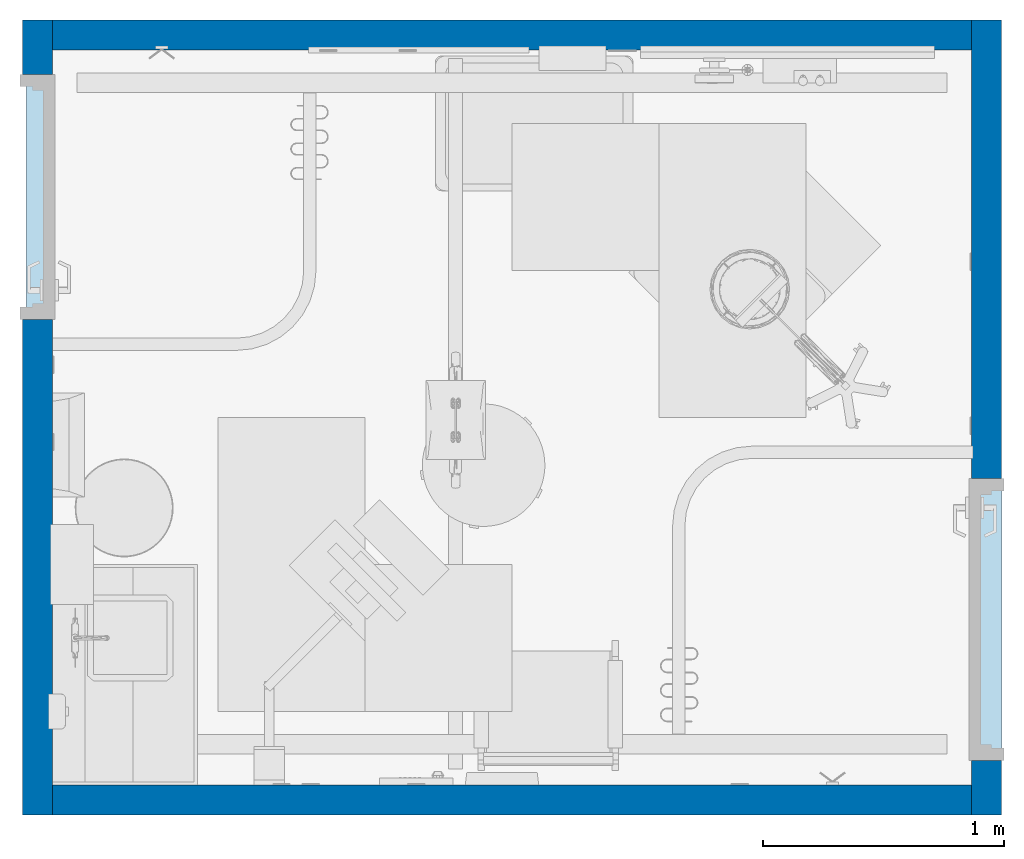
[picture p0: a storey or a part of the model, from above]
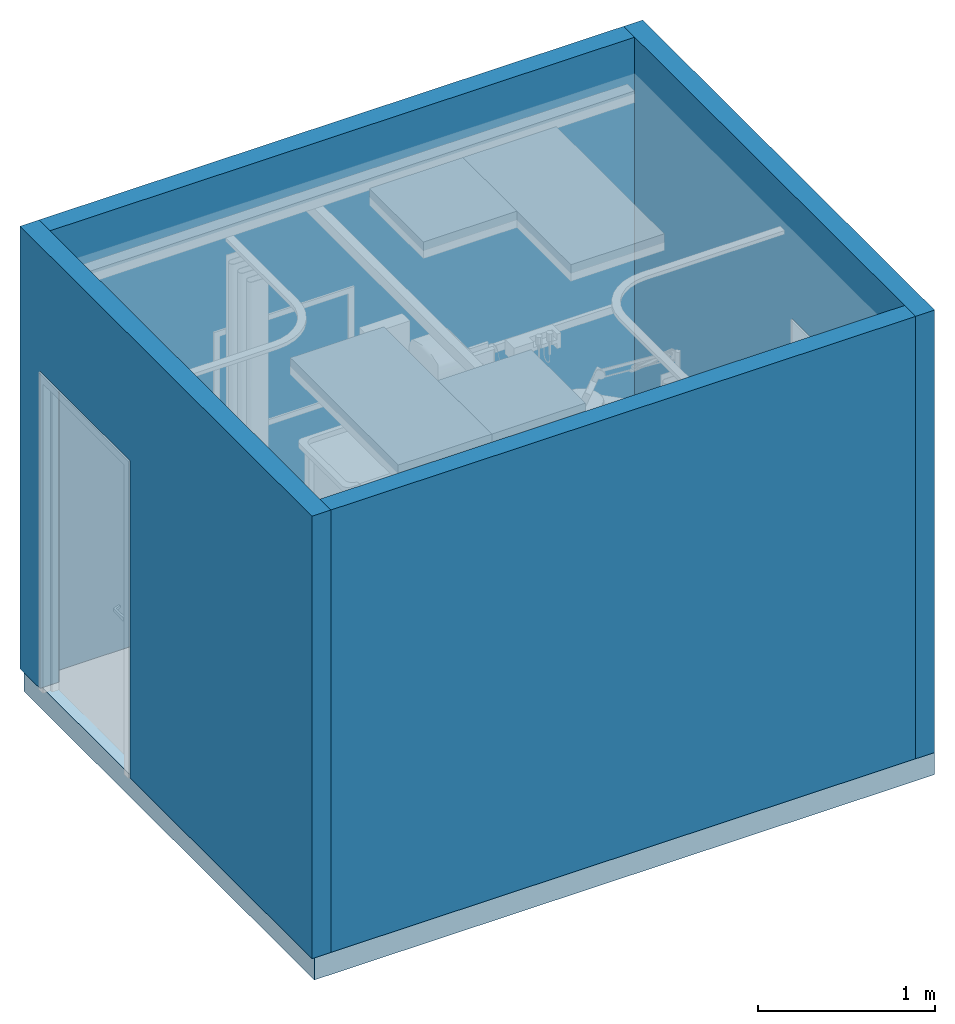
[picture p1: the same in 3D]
Properties of the parts of a building model (IFC2X3)

# File
Description: ViewDefinition [CoordinationView_V2.0]
File name: (ROOM CODE)
Time: 2018-06-27T14:00:12
Written by: The EXPRESS Data Manager Version 5.02.0100.07 : 28 Aug 2013
Made in: 20170223_1515(x64) - Exporter 18.0.0.420 - Alternate UI 18.0.0.420
Comment: STEP Physical File produced by: The EXPRESS Data Manager Version 5.02.0100.07 : 28 Aug 2013 * Module: EDMstepFileFactory/EDMstandAlone * Creation date: Wed Jun 27 14:00:12 2018 * Host: L106-OKC * Database: C:\Users\BHR~1.SPU\AppData\Local\Temp\{045EDBB5-DE35-4E17-B63D-0D913D50125E}\ifc * Database version: 5507 * Database creation date: Wed Jun 27 14:00:10 2018 * Schema: IFC2X3 * Model: DataRepository.ifc * Model creation date: Wed Jun 27 14:00:10 2018 * Header model: DataRepository.ifc_HeaderModel * Header model creation date: Wed Jun 27 14:00:10 2018 * EDMuser: sdai-user * EDMgroup: sdai-group * License ID and type: 5605 : Permanent license. Expiry date: * EDMstepFileFactory options: 020000

# IfcProject, (ROOM CODE)
LongName: ROOM NAME (ROOM CODE); Phase: DRAFT

# IfcSite, Default
RefLatitude: 42, 21, 31, 181945; RefLongitude: -71, -3, -24, -263305; RefElevation: 0 ft

# IfcBuilding, OUTPATIENT / PACT CLINIC (Ch. 265)
LongName: OUTPATIENT / PACT CLINIC (Ch. 265)
Pset_BuildingCommon - NumberOfStoreys: 1

# IfcBuildingStorey, DATUM
In: OUTPATIENT / PACT CLINIC (Ch. 265)
LongName: DATUM; Elevation: 0 ft

# IfcSpace, EXPA1
In: DATUM
LongName: EXAM ROOM-PATIENT ALIGNED CARE TEAM; InteriorOrExteriorSpace: INTERNAL
Pset_SpaceCommon - Reference: EXAM ROOM-PATIENT ALIGNED CARE TEAM EXPA1; Category: Rooms

# IfcBuildingElementProxy: 24" x 24", Supply Diffuser:24" x 24":721201
In: EXPA1
Type - Classification: D3040100 Air Distribution Systems (Uniformat)
Pset_BuildingElementProxyCommon - Reference: 24" x 24"

# IfcBuildingElementProxy: 24" x 24", Return Register:24" x 24":721202
In: EXPA1
Type - Classification: D3040200 Exhaust Ventilation Systems (Uniformat)
Pset_BuildingElementProxyCommon - Reference: 24" x 24"

# IfcBuildingElementProxy: 24"H x 24"D x 36"W, Z1018 - Cabinet, ADA Sink Support:24"H x 24"D x 36"W:1427568
In: EXPA1
Type - Classification: CC (Uniformat)
Pset_BuildingElementProxyCommon - Reference: 24"H x 24"D x 36"W
Pset_ManufacturerTypeInformation - Manufacturer: Herman Miller, Inc.

# IfcBuildingElementProxy: A1012 - Telephone, Wall Mounted, 1 Line 12'' x 12'', A1012 - Telephone, Wall Mounted, 1 Line:A1012 - Telephone, Wall Mounted, 1 Line 12'' x 12'':721190
In: EXPA1
Type - Classification: VV (Uniformat)
Pset_BuildingElementProxyCommon - Reference: A1012 - Telephone, Wall Mounted, 1 Line 12'' x 12''

# IfcBuildingElementProxy: A1132 - Rail, Accessory Mounting, A1132 - Rail, Accessory Mounting:A1132 - Rail, Accessory Mounting:721204
In: EXPA1
Type - Classification: VC (Uniformat)
Pset_BuildingElementProxyCommon - Reference: A1132 - Rail, Accessory Mounting

# IfcBuildingElementProxy: A1203 Lift System, Overhead, Bariatric, A1203 Lift System, Overhead, Bariatric (Traverse):A1203 Lift System, Overhead, Bariatric:1360987
In: EXPA1
Type - Classification: CC (Uniformat)
Pset_BuildingElementProxyCommon - Reference: A1203 Lift System, Overhead, Bariatric

# IfcBuildingElementProxy: A5075 - Dispenser, Soap, A5075 - Dispenser, Soap:A5075 - Dispenser, Soap:721176
In: EXPA1
Type - Classification: VV (Uniformat)
Pset_BuildingElementProxyCommon - Reference: A5075 - Dispenser, Soap

# IfcBuildingElementProxy: A5080 - Dispenser, Paper Towel, A5080 - Dispenser, Paper Towel:A5080 - Dispenser, Paper Towel:721177
In: EXPA1
Type - Classification: CC (Uniformat)
Pset_BuildingElementProxyCommon - Reference: A5080 - Dispenser, Paper Towel

# IfcBuildingElementProxy: A5107 - Dispenser, Glove, Surgical-Examination, Wall Mntd 10"x 4", A5107 - Dispenser, Glove, Surgical-Examination, Wall Mntd:A5107 - Dispenser, Glove, Surgical-Examination, Wall Mntd 10"x 4":721206
In: EXPA1
Classification: VV (Uniformat)
Pset_BuildingElementProxyCommon - Reference: A5107 - Dispenser, Glove, Surgical-Examination, Wall Mntd 10"x 4"

# IfcBuildingElementProxy: A5108 - Waste Disposal Unit, Sharps 17"x 13", A5108 - Waste Disposal Unit, Sharps:A5108 - Waste Disposal Unit, Sharps 17"x 13":1367652
In: DATUM
Type - Classification: VV (Uniformat)
Pset_BuildingElementProxyCommon - Reference: A5108 - Waste Disposal Unit, Sharps 17"x 13"

# IfcBuildingElementProxy: A5145 - Hook, Garment, Double (2)
In: EXPA1
Type - Classification: CC (Uniformat)
Pset_BuildingElementProxyCommon - Reference: A5145 - Hook, Garment, Double
Name (A5145 - Hook, Garment, Double:A5145 - Hook, Garment, Double:...)
721192
721203

# IfcBuildingElementProxy: A5180 - Track, Cubicle, Surface Mounted, With Curtain, Curved (2)
In: EXPA1
Type - Classification: CC (Uniformat)
Pset_BuildingElementProxyCommon - Reference: A5180 - Track, Cubicle, Surface Mounted, With Curtain, Curved
Name (A5180 - Track, Cubicle, Surface Mounted, With Curtain, Corner:A5180 - Track, Cubicle, Surface Mounted, With Curtain, Curved:...)
721171
721197

# IfcBuildingElementProxy: CD040 - Cabinet, W-H, 2 Shelf, 2 DO, Sloping Top, 38x36x13, CD040 - Cabinet, W-H, 2 Shelf, 2 DO, Sloping Top, 38x36x13:CD040 - Cabinet, W-H, 2 Shelf, 2 DO, Sloping Top, 38x36x13:721159
In: EXPA1
Type - Classification: CC (Uniformat)
Pset_BuildingElementProxyCommon - Reference: CD040 - Cabinet, W-H, 2 Shelf, 2 DO, Sloping Top, 38x36x13

# IfcBuildingElementProxy: CS010 - Sink, SS, Single Compartment, 7.5x12x12 ID, CS010 - Sink, SS, Single Compartment, 7.5x12x12 ID:CS010 - Sink, SS, Single Compartment, 7.5x12x12 ID:721198
In: EXPA1
Type - Classification: CC (Uniformat)
Pset_BuildingElementProxyCommon - Reference: CS010 - Sink, SS, Single Compartment, 7.5x12x12 ID

# IfcBuildingElementProxy: CT020 - Countertop, Solid Surface - No Opening (1), CT020 - Countertop, Solid Surface - No Opening (1):CT020 - Countertop, Solid Surface - No Opening (1):721196
In: EXPA1
Type - Classification: CC (Uniformat)
Pset_BuildingElementProxyCommon - Reference: CT020 - Countertop, Solid Surface - No Opening (1)

# IfcBuildingElementProxy: Dimmer (2)
In: EXPA1
Pset_BuildingElementProxyCommon - Reference: Dimmer
Name (Switch, Dimmer:Dimmer:...)
1554813
1554932

# IfcBuildingElementProxy: Duplex (5)
In: EXPA1
Pset_BuildingElementProxyCommon - Reference: Duplex
Name (Outlet, Duplex, Wall:Duplex:...)
1554962
1554978
1554994
1555037
1682465

# IfcBuildingElementProxy: E0948 - Cart, General Storage, Mobile 42x32x22, E0948 - Cart, General Storage, Mobile 42x32x22:E0948 - Cart, General Storage, Mobile 42x32x22:721178
In: EXPA1
Type - Classification: VV (Uniformat)
Pset_BuildingElementProxyCommon - Reference: E0948 - Cart, General Storage, Mobile 42x32x22

# IfcBuildingElementProxy: Exam/Treatment Table with Cabinet, M9025 - Exam Table:Exam/Treatment Table with Cabinet:721184
In: EXPA1
Type - Classification: VV (Uniformat)
Pset_BuildingElementProxyCommon - Reference: Exam/Treatment Table with Cabinet

# IfcBuildingElementProxy: F0205 - Chair, Side With Arms, F0205 - Chair, Side With Arms:F0205 - Chair, Side With Arms:721193
In: EXPA1
Type - Classification: VV (Uniformat)
Pset_BuildingElementProxyCommon - Reference: F0205 - Chair, Side With Arms

# IfcBuildingElementProxy: F0340 - Stool, Self Adjusting, F0340 - Stool, Self Adjusting:F0340 - Stool, Self Adjusting:721179
In: EXPA1
Type - Classification: VV (Uniformat)
Pset_BuildingElementProxyCommon - Reference: F0340 - Stool, Self Adjusting

# IfcBuildingElementProxy: F2000 - Basket, Wastepaper, F2000 - Basket, Wastepaper:F2000 - Basket, Wastepaper:721180
In: EXPA1
Type - Classification: VV (Uniformat)
Pset_BuildingElementProxyCommon - Reference: F2000 - Basket, Wastepaper

# IfcBuildingElementProxy: F3025 - Board, Bulletin, Wood Framed, F3025 - Board, Bulletin, Wood Framed:F3025 - Board, Bulletin, Wood Framed:721172
In: DATUM
Type - Classification: VV (Uniformat)
Pset_BuildingElementProxyCommon - Reference: F3025 - Board, Bulletin, Wood Framed

# IfcBuildingElementProxy: F3200 - Clock, Battery, 12in Dia, F3200 - Clock, Battery, 12in Dia:F3200 - Clock, Battery, 12in Dia:721181
In: EXPA1
Type - Classification: VV (Uniformat)
Pset_BuildingElementProxyCommon - Reference: F3200 - Clock, Battery, 12in Dia

# IfcBuildingElementProxy: Hoist, Hoist:Hoist:1360988
In: EXPA1
Pset_BuildingElementProxyCommon - Reference: Hoist

# IfcBuildingElementProxy: M1801 - Computer with Flat Panel Monitor, M1801 - Computer with Flat Panel Monitor:M1801 - Computer with Flat Panel Monitor:721170
In: EXPA1
Type - Classification: VV (Uniformat)
Pset_BuildingElementProxyCommon - Reference: M1801 - Computer with Flat Panel Monitor

# IfcBuildingElementProxy: M1803 - Workstation, Computer, Wall Mounted, M1803 - Workstation, Computer, Wall Mounted:M1803 - Workstation, Computer, Wall Mounted:721194
In: EXPA1
Type - Classification: VV (Uniformat)
Pset_BuildingElementProxyCommon - Reference: M1803 - Workstation, Computer, Wall Mounted

# IfcBuildingElementProxy: M4100 - Sphygmomanometer, Aneroid, Wall-Mounted, M4100 - Sphygmomanometer, Aneroid, Wall-Mounted:M4100 - Sphygmomanometer, Aneroid, Wall-Mounted:721182
In: EXPA1
Type - Classification: VV (Uniformat)
Pset_BuildingElementProxyCommon - Reference: M4100 - Sphygmomanometer, Aneroid, Wall-Mounted

# IfcBuildingElementProxy: M4200 - Otoscope_Ophthalmoscope, Wall Mounted, M4200 - Otoscope_Ophthalmoscope, Wall Mounted:M4200 - Otoscope_Ophthalmoscope, Wall Mounted:721183
In: EXPA1
Type - Classification: VV (Uniformat)
Pset_BuildingElementProxyCommon - Reference: M4200 - Otoscope_Ophthalmoscope, Wall Mounted

# IfcBuildingElementProxy: Mobile Spotlight, Mobile Stand, M7401 - Exam Light:Mobile Spotlight, Mobile Stand:721173
In: EXPA1
Type - Classification: VV (Uniformat)
Pset_BuildingElementProxyCommon - Reference: Mobile Spotlight, Mobile Stand

# IfcBuildingElementProxy: Quadraplex, Outlet, Quadraplex, Wall:Quadraplex:1813640
In: EXPA1
Pset_BuildingElementProxyCommon - Reference: Quadraplex

# IfcBuildingElementProxy: Telephone/Data (3)
In: EXPA1
Pset_BuildingElementProxyCommon - Reference: Telephone/Data
Name (Outlet, Communications:Telephone/Data:...)
1554857
1813686
1941075

# IfcCovering: Compound Ceiling:2' x 2' ACT System, Compound Ceiling:2' x 2' ACT System:721146
In: DATUM
PredefinedType: CEILING; Classification: C3030210 Suspended Ceilings - Acoustical (Uniformat); Material: <Unnamed> 0.135417 ft, Acoustic Ceiling Tile 24 x 24 0.0520833 ft
Pset_CoveringCommon - Reference: 2' x 2' ACT System; Finish: Acoustic Ceiling Tile 24 x 24;; TotalThickness: 0.1875 ft

# IfcDoor: 36" x 84", Single - Flush:36" x 84":1508667
In: DATUM
Type - ParameterTakesPrecedence: no; Sizeable: no; Classification: C1020 Interior Doors (Uniformat)
OverallHeight: 7.16667 ft; OverallWidth: 3.33333 ft
Pset_DoorCommon - IsExternal: no; Reference: 36" x 84"

# IfcDoor: 42" x 84", Single - Flush:42" x 84":1508666
In: DATUM
Type - ParameterTakesPrecedence: no; Sizeable: no; Classification: C1020 Interior Doors (Uniformat)
OverallHeight: 7.16667 ft; OverallWidth: 3.83333 ft
Pset_DoorCommon - IsExternal: no; Reference: 42" x 84"

# IfcFlowTerminal: 2'x4' (2)
In: EXPA1
Type - Classification: D5020210 Lighting - Fluorescent (Uniformat)
Pset_DistributionFlowElementCommon - Reference: 2'x4'
Name (Troffer Light:2'x4':...)
721200
1806949

# IfcSlab: Floor:Generic - 6", Floor:Generic - 6":721154
In: DATUM
PredefinedType: FLOOR; Classification: B1010 Floor Construction (Uniformat); Material: <Unnamed> 0.5 ft
Pset_SlabCommon - LoadBearing: no; Reference: Generic - 6"; IsExternal: no; PitchAngle: 0 deg

# IfcWallStandardCase: Basic Wall:Interior - 4 7/8" (4)
In: DATUM
Type - PredefinedType: STANDARD; Material: <Unnamed> 0.40625 ft
Classification: B2010 Exterior Walls (Uniformat)
Pset_WallCommon - Reference: Interior - 4 7/8"; LoadBearing: no; ExtendToStructure: no; IsExternal: yes
Name (Basic Wall:Interior - 4 7/8":...)
721137
721138
721139
721141
